VERSION 5.6 ;
BUSBITCHARS "[]" ;
DIVIDERCHAR "/" ;

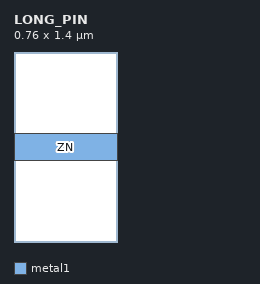
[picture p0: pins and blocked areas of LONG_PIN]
MACRO LONG_PIN
  CLASS CORE ;
  ORIGIN 0 0 ;
  SIZE 0.76 BY 1.4 ;
  SYMMETRY X Y ;
  SITE FreePDK45_38x28_10R_NP_162NW_34O ;
  PIN A1 
  END A1
  PIN A2 
  END A2
  PIN ZN
    DIRECTION INPUT ;
    PORT
      LAYER metal1 ;
        RECT 0 0.6 0.76 0.8  ;
    END 
  END ZN
  PIN VDD 
  END VDD
  PIN VSS 
  END VSS
END LONG_PIN
